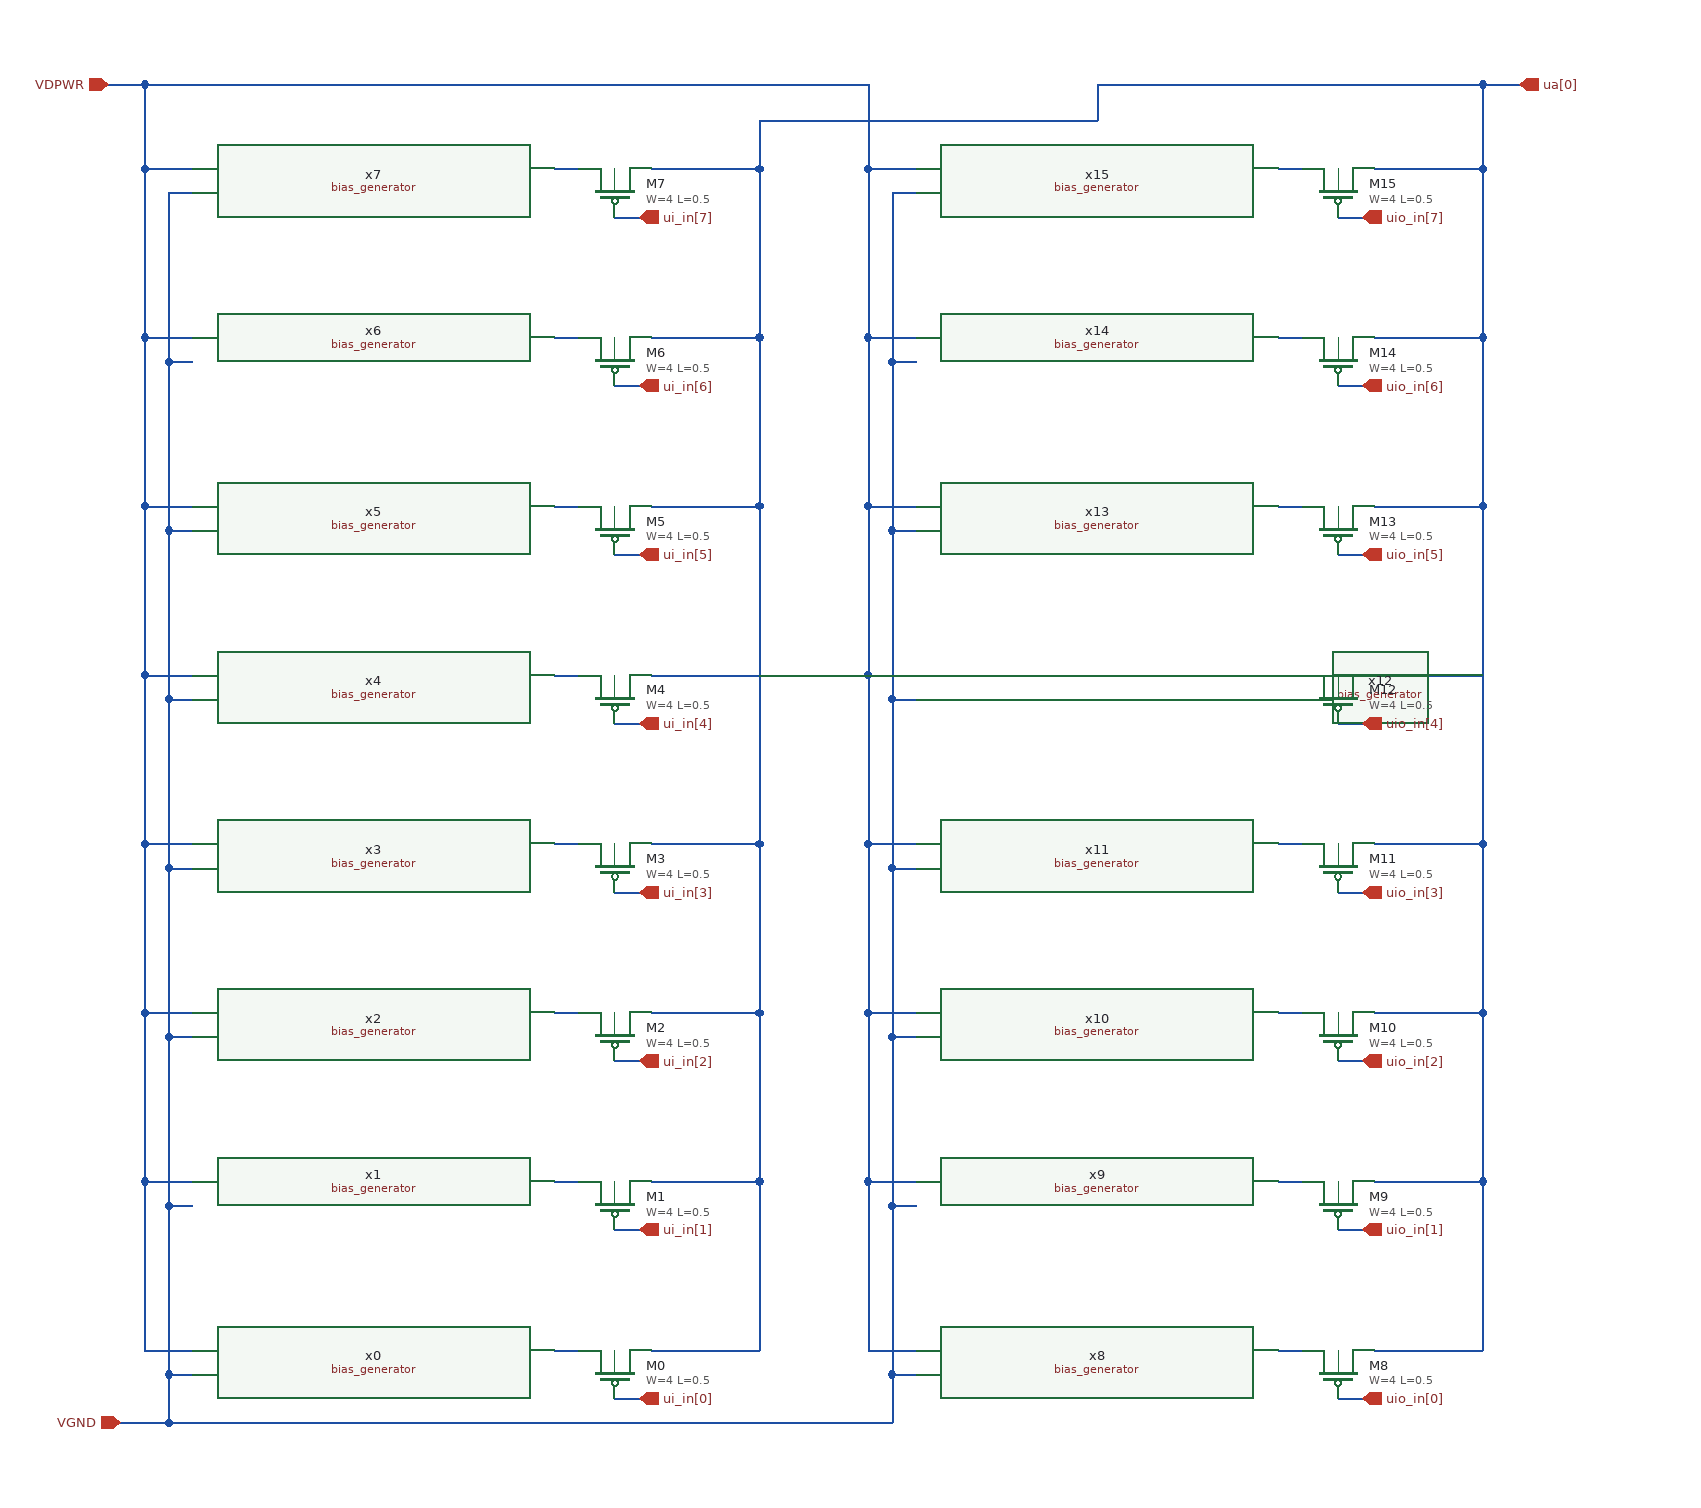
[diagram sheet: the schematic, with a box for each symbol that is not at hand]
v {xschem version=3.4.5 file_version=1.2
}
G {}
K {}
V {}
S {}
E {}
N 1350 -1290 1370 -1290 {
lab=#net1}
N 1400 -1250 1420 -1250 {
lab=ui_in[0]}
N 1350 -1570 1370 -1570 {
lab=#net2}
N 1400 -1530 1420 -1530 {
lab=ui_in[2]}
N 1350 -1430 1370 -1430 {
lab=#net3}
N 1400 -1390 1420 -1390 {
lab=ui_in[1]}
N 1350 -1710 1370 -1710 {
lab=#net4}
N 1400 -1670 1420 -1670 {
lab=ui_in[3]}
N 1350 -1850 1370 -1850 {
lab=#net5}
N 1400 -1810 1420 -1810 {
lab=ui_in[4]}
N 1350 -1990 1370 -1990 {
lab=#net6}
N 1400 -1950 1420 -1950 {
lab=ui_in[5]}
N 1350 -2130 1370 -2130 {
lab=#net7}
N 1400 -2090 1420 -2090 {
lab=ui_in[6]}
N 1350 -2270 1370 -2270 {
lab=#net8}
N 1400 -2230 1420 -2230 {
lab=ui_in[7]}
N 1950 -1290 1970 -1290 {
lab=#net9}
N 2000 -1250 2020 -1250 {
lab=uio_in[0]}
N 1950 -1430 1970 -1430 {
lab=#net10}
N 2000 -1390 2020 -1390 {
lab=uio_in[1]}
N 1950 -1570 1970 -1570 {
lab=#net11}
N 2000 -1530 2020 -1530 {
lab=uio_in[2]}
N 1950 -1710 1970 -1710 {
lab=#net12}
N 2000 -1670 2020 -1670 {
lab=uio_in[3]}
N 1950 -1850 1970 -1850 {
lab=#net13}
N 2000 -1810 2020 -1810 {
lab=uio_in[4]}
N 1950 -1990 1970 -1990 {
lab=#net14}
N 2000 -1950 2020 -1950 {
lab=uio_in[5]}
N 1950 -2130 1970 -2130 {
lab=#net15}
N 2000 -2090 2020 -2090 {
lab=uio_in[6]}
N 1950 -2270 1970 -2270 {
lab=#net16}
N 2000 -2230 2020 -2230 {
lab=uio_in[7]}
N 1030 -1270 1050 -1270 {
lab=VGND}
N 1030 -1410 1030 -1270 {
lab=VGND}
N 1030 -1410 1050 -1410 {
lab=VGND}
N 1030 -1410 1050 -1410 {
lab=VGND}
N 1030 -1550 1030 -1410 {
lab=VGND}
N 1030 -1550 1050 -1550 {
lab=VGND}
N 1030 -1690 1030 -1550 {
lab=VGND}
N 1030 -1690 1050 -1690 {
lab=VGND}
N 1010 -1290 1050 -1290 {
lab=VDPWR}
N 1010 -1430 1010 -1290 {
lab=VDPWR}
N 1010 -1430 1050 -1430 {
lab=VDPWR}
N 1010 -1570 1010 -1430 {
lab=VDPWR}
N 1010 -1570 1050 -1570 {
lab=VDPWR}
N 1030 -1830 1030 -1690 {
lab=VGND}
N 1030 -1830 1050 -1830 {
lab=VGND}
N 1010 -1710 1010 -1570 {
lab=VDPWR}
N 1010 -1710 1050 -1710 {
lab=VDPWR}
N 1030 -1970 1030 -1830 {
lab=VGND}
N 1030 -1970 1050 -1970 {
lab=VGND}
N 1030 -2110 1030 -1970 {
lab=VGND}
N 1030 -2110 1050 -2110 {
lab=VGND}
N 1030 -2110 1050 -2110 {
lab=VGND}
N 1030 -2250 1030 -2110 {
lab=VGND}
N 1030 -2250 1050 -2250 {
lab=VGND}
N 1010 -1850 1010 -1710 {
lab=VDPWR}
N 1010 -1850 1050 -1850 {
lab=VDPWR}
N 1010 -1990 1010 -1850 {
lab=VDPWR}
N 1010 -1990 1050 -1990 {
lab=VDPWR}
N 1010 -2130 1010 -1990 {
lab=VDPWR}
N 1010 -2130 1050 -2130 {
lab=VDPWR}
N 1010 -2270 1010 -2130 {
lab=VDPWR}
N 1010 -2270 1050 -2270 {
lab=VDPWR}
N 1630 -1270 1650 -1270 {
lab=VGND}
N 1630 -1410 1630 -1270 {
lab=VGND}
N 1630 -1410 1650 -1410 {
lab=VGND}
N 1630 -1410 1650 -1410 {
lab=VGND}
N 1630 -1550 1630 -1410 {
lab=VGND}
N 1630 -1550 1650 -1550 {
lab=VGND}
N 1630 -1690 1630 -1550 {
lab=VGND}
N 1630 -1690 1650 -1690 {
lab=VGND}
N 1610 -1290 1650 -1290 {
lab=VDPWR}
N 1610 -1430 1610 -1290 {
lab=VDPWR}
N 1610 -1430 1650 -1430 {
lab=VDPWR}
N 1610 -1570 1610 -1430 {
lab=VDPWR}
N 1610 -1570 1650 -1570 {
lab=VDPWR}
N 1630 -1830 1630 -1690 {
lab=VGND}
N 1630 -1830 1650 -1830 {
lab=VGND}
N 1610 -1710 1610 -1570 {
lab=VDPWR}
N 1610 -1710 1650 -1710 {
lab=VDPWR}
N 1630 -1970 1630 -1830 {
lab=VGND}
N 1630 -1970 1650 -1970 {
lab=VGND}
N 1630 -2110 1630 -1970 {
lab=VGND}
N 1630 -2110 1650 -2110 {
lab=VGND}
N 1630 -2110 1650 -2110 {
lab=VGND}
N 1630 -2250 1630 -2110 {
lab=VGND}
N 1630 -2250 1650 -2250 {
lab=VGND}
N 1610 -1850 1610 -1710 {
lab=VDPWR}
N 1610 -1850 1650 -1850 {
lab=VDPWR}
N 1610 -1990 1610 -1850 {
lab=VDPWR}
N 1610 -1990 1650 -1990 {
lab=VDPWR}
N 1610 -2130 1610 -1990 {
lab=VDPWR}
N 1610 -2130 1650 -2130 {
lab=VDPWR}
N 1610 -2270 1610 -2130 {
lab=VDPWR}
N 1610 -2270 1650 -2270 {
lab=VDPWR}
N 1610 -2340 1610 -2270 {
lab=VDPWR}
N 1010 -2340 1610 -2340 {
lab=VDPWR}
N 1010 -2340 1010 -2270 {
lab=VDPWR}
N 1030 -1270 1030 -1230 {
lab=VGND}
N 1030 -1230 1630 -1230 {
lab=VGND}
N 1630 -1270 1630 -1230 {
lab=VGND}
N 980 -2340 1010 -2340 {
lab=VDPWR}
N 990 -1230 1030 -1230 {
lab=VGND}
N 1430 -2270 1520 -2270 {
lab=ua[0]}
N 1520 -2270 1520 -2130 {
lab=ua[0]}
N 1430 -2130 1520 -2130 {
lab=ua[0]}
N 1430 -1850 1520 -1850 {
lab=ua[0]}
N 1430 -1990 1520 -1990 {
lab=ua[0]}
N 1520 -1860 1520 -1710 {
lab=ua[0]}
N 1430 -1710 1520 -1710 {
lab=ua[0]}
N 1520 -1710 1520 -1570 {
lab=ua[0]}
N 1430 -1570 1520 -1570 {
lab=ua[0]}
N 1520 -1570 1520 -1430 {
lab=ua[0]}
N 1430 -1430 1520 -1430 {
lab=ua[0]}
N 1520 -1430 1520 -1290 {
lab=ua[0]}
N 1430 -1290 1520 -1290 {
lab=ua[0]}
N 1520 -2130 1520 -1990 {
lab=ua[0]}
N 1520 -1990 1520 -1860 {
lab=ua[0]}
N 2030 -2270 2120 -2270 {
lab=ua[0]}
N 2120 -2270 2120 -2130 {
lab=ua[0]}
N 2030 -2130 2120 -2130 {
lab=ua[0]}
N 2030 -1850 2120 -1850 {
lab=ua[0]}
N 2030 -1990 2120 -1990 {
lab=ua[0]}
N 2120 -1860 2120 -1710 {
lab=ua[0]}
N 2030 -1710 2120 -1710 {
lab=ua[0]}
N 2120 -1710 2120 -1570 {
lab=ua[0]}
N 2030 -1570 2120 -1570 {
lab=ua[0]}
N 2120 -1570 2120 -1430 {
lab=ua[0]}
N 2030 -1430 2120 -1430 {
lab=ua[0]}
N 2120 -1430 2120 -1290 {
lab=ua[0]}
N 2030 -1290 2120 -1290 {
lab=ua[0]}
N 2120 -2130 2120 -1990 {
lab=ua[0]}
N 2120 -1990 2120 -1860 {
lab=ua[0]}
N 2120 -2340 2120 -2270 {
lab=ua[0]}
N 1520 -2310 1520 -2270 {
lab=ua[0]}
N 1520 -2310 1640 -2310 {
lab=ua[0]}
N 1800 -2340 1800 -2310 {
lab=ua[0]}
N 1640 -2310 1800 -2310 {
lab=ua[0]}
N 1800 -2340 2120 -2340 {
lab=ua[0]}
N 2120 -2340 2150 -2340 {
lab=ua[0]}
C {/foss/designs/tt08-analog-bias-generator/xschem/bias_generator.sym} 1200 -1280 0 0 {name=x0}
C {/foss/designs/tt08-analog-bias-generator/xschem/bias_generator.sym} 1200 -1420 0 0 {name=x1}
C {/foss/designs/tt08-analog-bias-generator/xschem/bias_generator.sym} 1200 -1560 0 0 {name=x2}
C {/foss/designs/tt08-analog-bias-generator/xschem/bias_generator.sym} 1200 -1700 0 0 {name=x3}
C {/foss/designs/tt08-analog-bias-generator/xschem/bias_generator.sym} 1200 -1840 0 0 {name=x4}
C {/foss/designs/tt08-analog-bias-generator/xschem/bias_generator.sym} 1200 -1980 0 0 {name=x5}
C {/foss/designs/tt08-analog-bias-generator/xschem/bias_generator.sym} 1200 -2120 0 0 {name=x6}
C {/foss/designs/tt08-analog-bias-generator/xschem/bias_generator.sym} 1200 -2260 0 0 {name=x7}
C {/foss/designs/tt08-analog-bias-generator/xschem/bias_generator.sym} 1800 -1280 0 0 {name=x8}
C {/foss/designs/tt08-analog-bias-generator/xschem/bias_generator.sym} 1800 -1420 0 0 {name=x9}
C {/foss/designs/tt08-analog-bias-generator/xschem/bias_generator.sym} 1800 -1560 0 0 {name=x10}
C {/foss/designs/tt08-analog-bias-generator/xschem/bias_generator.sym} 1800 -1700 0 0 {name=x11}
C {/foss/designs/tt08-analog-bias-generator/xschem/bias_generator.sym} 1800 -1840 0 0 {name=x12}
C {/foss/designs/tt08-analog-bias-generator/xschem/bias_generator.sym} 1800 -1980 0 0 {name=x13}
C {/foss/designs/tt08-analog-bias-generator/xschem/bias_generator.sym} 1800 -2120 0 0 {name=x14}
C {/foss/designs/tt08-analog-bias-generator/xschem/bias_generator.sym} 1800 -2260 0 0 {name=x15}
C {sky130_fd_pr/pfet3_01v8.sym} 1400 -1270 3 0 {name=M0
L=0.5
W=4
body=VDPWR
nf=1
mult=1
ad="'int((nf+1)/2) * W/nf * 0.29'" 
pd="'2*int((nf+1)/2) * (W/nf + 0.29)'"
as="'int((nf+2)/2) * W/nf * 0.29'" 
ps="'2*int((nf+2)/2) * (W/nf + 0.29)'"
nrd="'0.29 / W'" nrs="'0.29 / W'"
sa=0 sb=0 sd=0
model=pfet_01v8
spiceprefix=X
}
C {devices/ipin.sym} 1420 -1250 0 1 {name=p1 lab=ui_in[0]}
C {sky130_fd_pr/pfet3_01v8.sym} 1400 -1550 3 0 {name=M2
L=0.5
W=4
body=VDPWR
nf=1
mult=1
ad="'int((nf+1)/2) * W/nf * 0.29'" 
pd="'2*int((nf+1)/2) * (W/nf + 0.29)'"
as="'int((nf+2)/2) * W/nf * 0.29'" 
ps="'2*int((nf+2)/2) * (W/nf + 0.29)'"
nrd="'0.29 / W'" nrs="'0.29 / W'"
sa=0 sb=0 sd=0
model=pfet_01v8
spiceprefix=X
}
C {devices/ipin.sym} 1420 -1530 0 1 {name=p2 lab=ui_in[2]}
C {sky130_fd_pr/pfet3_01v8.sym} 1400 -1410 3 0 {name=M1
L=0.5
W=4
body=VDPWR
nf=1
mult=1
ad="'int((nf+1)/2) * W/nf * 0.29'" 
pd="'2*int((nf+1)/2) * (W/nf + 0.29)'"
as="'int((nf+2)/2) * W/nf * 0.29'" 
ps="'2*int((nf+2)/2) * (W/nf + 0.29)'"
nrd="'0.29 / W'" nrs="'0.29 / W'"
sa=0 sb=0 sd=0
model=pfet_01v8
spiceprefix=X
}
C {devices/ipin.sym} 1420 -1390 0 1 {name=p3 lab=ui_in[1]}
C {sky130_fd_pr/pfet3_01v8.sym} 1400 -1690 3 0 {name=M3
L=0.5
W=4
body=VDPWR
nf=1
mult=1
ad="'int((nf+1)/2) * W/nf * 0.29'" 
pd="'2*int((nf+1)/2) * (W/nf + 0.29)'"
as="'int((nf+2)/2) * W/nf * 0.29'" 
ps="'2*int((nf+2)/2) * (W/nf + 0.29)'"
nrd="'0.29 / W'" nrs="'0.29 / W'"
sa=0 sb=0 sd=0
model=pfet_01v8
spiceprefix=X
}
C {devices/ipin.sym} 1420 -1670 0 1 {name=p4 lab=ui_in[3]}
C {sky130_fd_pr/pfet3_01v8.sym} 1400 -1830 3 0 {name=M4
L=0.5
W=4
body=VDPWR
nf=1
mult=1
ad="'int((nf+1)/2) * W/nf * 0.29'" 
pd="'2*int((nf+1)/2) * (W/nf + 0.29)'"
as="'int((nf+2)/2) * W/nf * 0.29'" 
ps="'2*int((nf+2)/2) * (W/nf + 0.29)'"
nrd="'0.29 / W'" nrs="'0.29 / W'"
sa=0 sb=0 sd=0
model=pfet_01v8
spiceprefix=X
}
C {devices/ipin.sym} 1420 -1810 0 1 {name=p5 lab=ui_in[4]}
C {sky130_fd_pr/pfet3_01v8.sym} 1400 -1970 3 0 {name=M5
L=0.5
W=4
body=VDPWR
nf=1
mult=1
ad="'int((nf+1)/2) * W/nf * 0.29'" 
pd="'2*int((nf+1)/2) * (W/nf + 0.29)'"
as="'int((nf+2)/2) * W/nf * 0.29'" 
ps="'2*int((nf+2)/2) * (W/nf + 0.29)'"
nrd="'0.29 / W'" nrs="'0.29 / W'"
sa=0 sb=0 sd=0
model=pfet_01v8
spiceprefix=X
}
C {devices/ipin.sym} 1420 -1950 0 1 {name=p6 lab=ui_in[5]}
C {sky130_fd_pr/pfet3_01v8.sym} 1400 -2110 3 0 {name=M6
L=0.5
W=4
body=VDPWR
nf=1
mult=1
ad="'int((nf+1)/2) * W/nf * 0.29'" 
pd="'2*int((nf+1)/2) * (W/nf + 0.29)'"
as="'int((nf+2)/2) * W/nf * 0.29'" 
ps="'2*int((nf+2)/2) * (W/nf + 0.29)'"
nrd="'0.29 / W'" nrs="'0.29 / W'"
sa=0 sb=0 sd=0
model=pfet_01v8
spiceprefix=X
}
C {devices/ipin.sym} 1420 -2090 0 1 {name=p7 lab=ui_in[6]}
C {sky130_fd_pr/pfet3_01v8.sym} 1400 -2250 3 0 {name=M7
L=0.5
W=4
body=VDPWR
nf=1
mult=1
ad="'int((nf+1)/2) * W/nf * 0.29'" 
pd="'2*int((nf+1)/2) * (W/nf + 0.29)'"
as="'int((nf+2)/2) * W/nf * 0.29'" 
ps="'2*int((nf+2)/2) * (W/nf + 0.29)'"
nrd="'0.29 / W'" nrs="'0.29 / W'"
sa=0 sb=0 sd=0
model=pfet_01v8
spiceprefix=X
}
C {devices/ipin.sym} 1420 -2230 0 1 {name=p8 lab=ui_in[7]}
C {sky130_fd_pr/pfet3_01v8.sym} 2000 -1270 3 0 {name=M8
L=0.5
W=4
body=VDPWR
nf=1
mult=1
ad="'int((nf+1)/2) * W/nf * 0.29'" 
pd="'2*int((nf+1)/2) * (W/nf + 0.29)'"
as="'int((nf+2)/2) * W/nf * 0.29'" 
ps="'2*int((nf+2)/2) * (W/nf + 0.29)'"
nrd="'0.29 / W'" nrs="'0.29 / W'"
sa=0 sb=0 sd=0
model=pfet_01v8
spiceprefix=X
}
C {devices/ipin.sym} 2020 -1250 0 1 {name=p9 lab=uio_in[0]}
C {sky130_fd_pr/pfet3_01v8.sym} 2000 -1410 3 0 {name=M9
L=0.5
W=4
body=VDPWR
nf=1
mult=1
ad="'int((nf+1)/2) * W/nf * 0.29'" 
pd="'2*int((nf+1)/2) * (W/nf + 0.29)'"
as="'int((nf+2)/2) * W/nf * 0.29'" 
ps="'2*int((nf+2)/2) * (W/nf + 0.29)'"
nrd="'0.29 / W'" nrs="'0.29 / W'"
sa=0 sb=0 sd=0
model=pfet_01v8
spiceprefix=X
}
C {devices/ipin.sym} 2020 -1390 0 1 {name=p10 lab=uio_in[1]}
C {sky130_fd_pr/pfet3_01v8.sym} 2000 -1550 3 0 {name=M10
L=0.5
W=4
body=VDPWR
nf=1
mult=1
ad="'int((nf+1)/2) * W/nf * 0.29'" 
pd="'2*int((nf+1)/2) * (W/nf + 0.29)'"
as="'int((nf+2)/2) * W/nf * 0.29'" 
ps="'2*int((nf+2)/2) * (W/nf + 0.29)'"
nrd="'0.29 / W'" nrs="'0.29 / W'"
sa=0 sb=0 sd=0
model=pfet_01v8
spiceprefix=X
}
C {devices/ipin.sym} 2020 -1530 0 1 {name=p11 lab=uio_in[2]}
C {sky130_fd_pr/pfet3_01v8.sym} 2000 -1690 3 0 {name=M11
L=0.5
W=4
body=VDPWR
nf=1
mult=1
ad="'int((nf+1)/2) * W/nf * 0.29'" 
pd="'2*int((nf+1)/2) * (W/nf + 0.29)'"
as="'int((nf+2)/2) * W/nf * 0.29'" 
ps="'2*int((nf+2)/2) * (W/nf + 0.29)'"
nrd="'0.29 / W'" nrs="'0.29 / W'"
sa=0 sb=0 sd=0
model=pfet_01v8
spiceprefix=X
}
C {devices/ipin.sym} 2020 -1670 0 1 {name=p12 lab=uio_in[3]}
C {sky130_fd_pr/pfet3_01v8.sym} 2000 -1830 3 0 {name=M12
L=0.5
W=4
body=VDPWR
nf=1
mult=1
ad="'int((nf+1)/2) * W/nf * 0.29'" 
pd="'2*int((nf+1)/2) * (W/nf + 0.29)'"
as="'int((nf+2)/2) * W/nf * 0.29'" 
ps="'2*int((nf+2)/2) * (W/nf + 0.29)'"
nrd="'0.29 / W'" nrs="'0.29 / W'"
sa=0 sb=0 sd=0
model=pfet_01v8
spiceprefix=X
}
C {devices/ipin.sym} 2020 -1810 0 1 {name=p13 lab=uio_in[4]}
C {sky130_fd_pr/pfet3_01v8.sym} 2000 -1970 3 0 {name=M13
L=0.5
W=4
body=VDPWR
nf=1
mult=1
ad="'int((nf+1)/2) * W/nf * 0.29'" 
pd="'2*int((nf+1)/2) * (W/nf + 0.29)'"
as="'int((nf+2)/2) * W/nf * 0.29'" 
ps="'2*int((nf+2)/2) * (W/nf + 0.29)'"
nrd="'0.29 / W'" nrs="'0.29 / W'"
sa=0 sb=0 sd=0
model=pfet_01v8
spiceprefix=X
}
C {devices/ipin.sym} 2020 -1950 0 1 {name=p14 lab=uio_in[5]}
C {sky130_fd_pr/pfet3_01v8.sym} 2000 -2110 3 0 {name=M14
L=0.5
W=4
body=VDPWR
nf=1
mult=1
ad="'int((nf+1)/2) * W/nf * 0.29'" 
pd="'2*int((nf+1)/2) * (W/nf + 0.29)'"
as="'int((nf+2)/2) * W/nf * 0.29'" 
ps="'2*int((nf+2)/2) * (W/nf + 0.29)'"
nrd="'0.29 / W'" nrs="'0.29 / W'"
sa=0 sb=0 sd=0
model=pfet_01v8
spiceprefix=X
}
C {devices/ipin.sym} 2020 -2090 0 1 {name=p15 lab=uio_in[6]}
C {sky130_fd_pr/pfet3_01v8.sym} 2000 -2250 3 0 {name=M15
L=0.5
W=4
body=VDPWR
nf=1
mult=1
ad="'int((nf+1)/2) * W/nf * 0.29'" 
pd="'2*int((nf+1)/2) * (W/nf + 0.29)'"
as="'int((nf+2)/2) * W/nf * 0.29'" 
ps="'2*int((nf+2)/2) * (W/nf + 0.29)'"
nrd="'0.29 / W'" nrs="'0.29 / W'"
sa=0 sb=0 sd=0
model=pfet_01v8
spiceprefix=X
}
C {devices/ipin.sym} 2020 -2230 0 1 {name=p16 lab=uio_in[7]}
C {devices/ipin.sym} 980 -2340 0 0 {name=p17 lab=VDPWR}
C {devices/ipin.sym} 990 -1230 0 0 {name=p18 lab=VGND}
C {devices/opin.sym} 2150 -2340 0 0 {name=p19 lab=ua[0]}
